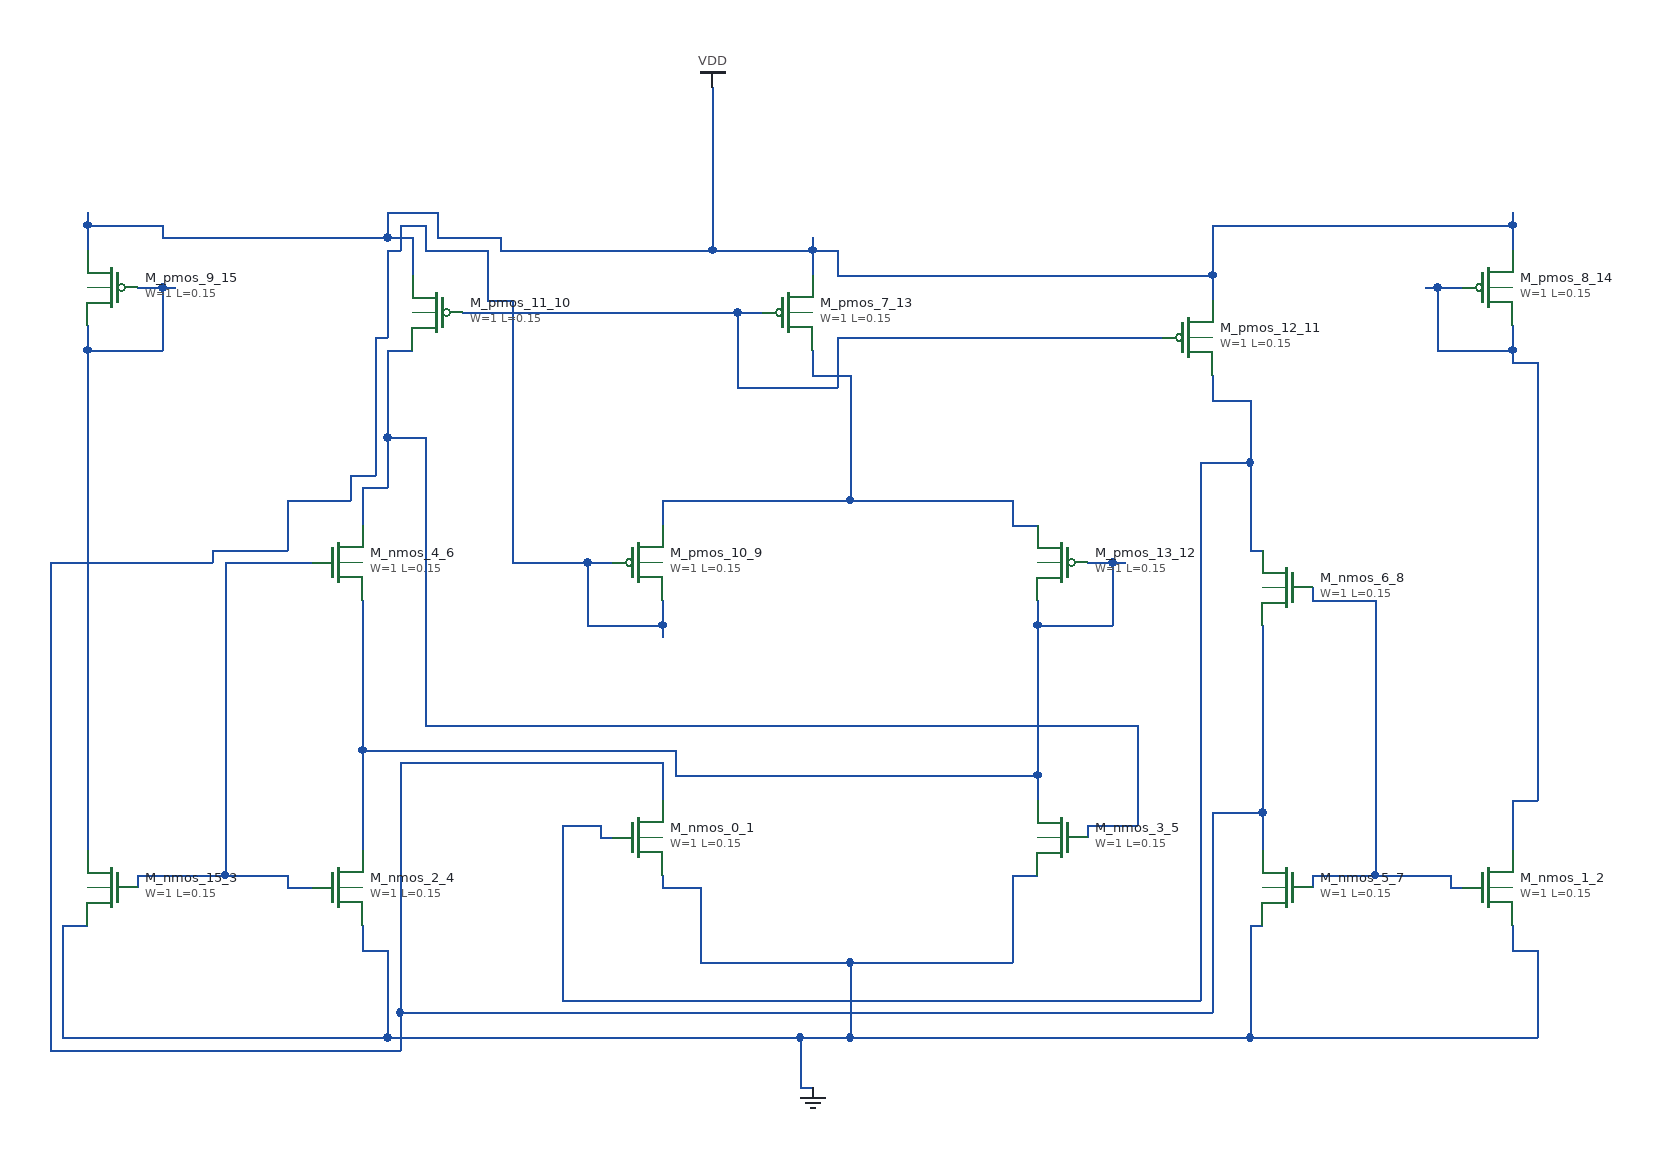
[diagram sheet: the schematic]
v {xschem version=3.4.8 file_version=1.2}
G {}
K {}
V {}
S {}
E {}
C {devices/gnd.sym} 660 880 0 0 {name="l_gnd_14_0" lab="GND"}
C {sky130_fd_pr/nfet3_01v8.sym} 520 680 0 0 {name="M_nmos_0_1"
W=1
L=0.15
body=GND
nf=1
mult=1
ad="expr('int((@nf + 1)/2) * @W / @nf * 0.29')"
pd="expr('2*int((@nf + 1)/2) * (@W / @nf + 0.29)')"
as="expr('int((@nf + 2)/2) * @W / @nf * 0.29')"
ps="expr('2*int((@nf + 2)/2) * (@W / @nf + 0.29)')"
nrd="expr('0.29 / @W ')" nrs="expr('0.29 / @W ')"
sa=0 sb=0 sd=0
model=nfet_01v8
spiceprefix=X
}
C {sky130_fd_pr/nfet3_01v8.sym} 1200 720 0 0 {name="M_nmos_1_2"
W=1
L=0.15
body=GND
nf=1
mult=1
ad="expr('int((@nf + 1)/2) * @W / @nf * 0.29')"
pd="expr('2*int((@nf + 1)/2) * (@W / @nf + 0.29)')"
as="expr('int((@nf + 2)/2) * @W / @nf * 0.29')"
ps="expr('2*int((@nf + 2)/2) * (@W / @nf + 0.29)')"
nrd="expr('0.29 / @W ')" nrs="expr('0.29 / @W ')"
sa=0 sb=0 sd=0
model=nfet_01v8
spiceprefix=X
}
C {sky130_fd_pr/nfet3_01v8.sym} 100 720 0 1 {name="M_nmos_15_3"
W=1
L=0.15
body=GND
nf=1
mult=1
ad="expr('int((@nf + 1)/2) * @W / @nf * 0.29')"
pd="expr('2*int((@nf + 1)/2) * (@W / @nf + 0.29)')"
as="expr('int((@nf + 2)/2) * @W / @nf * 0.29')"
ps="expr('2*int((@nf + 2)/2) * (@W / @nf + 0.29)')"
nrd="expr('0.29 / @W ')" nrs="expr('0.29 / @W ')"
sa=0 sb=0 sd=0
model=nfet_01v8
spiceprefix=X
}
C {sky130_fd_pr/nfet3_01v8.sym} 280 720 0 0 {name="M_nmos_2_4"
W=1
L=0.15
body=GND
nf=1
mult=1
ad="expr('int((@nf + 1)/2) * @W / @nf * 0.29')"
pd="expr('2*int((@nf + 1)/2) * (@W / @nf + 0.29)')"
as="expr('int((@nf + 2)/2) * @W / @nf * 0.29')"
ps="expr('2*int((@nf + 2)/2) * (@W / @nf + 0.29)')"
nrd="expr('0.29 / @W ')" nrs="expr('0.29 / @W ')"
sa=0 sb=0 sd=0
model=nfet_01v8
spiceprefix=X
}
C {sky130_fd_pr/nfet3_01v8.sym} 860 680 0 1 {name="M_nmos_3_5"
W=1
L=0.15
body=GND
nf=1
mult=1
ad="expr('int((@nf + 1)/2) * @W / @nf * 0.29')"
pd="expr('2*int((@nf + 1)/2) * (@W / @nf + 0.29)')"
as="expr('int((@nf + 2)/2) * @W / @nf * 0.29')"
ps="expr('2*int((@nf + 2)/2) * (@W / @nf + 0.29)')"
nrd="expr('0.29 / @W ')" nrs="expr('0.29 / @W ')"
sa=0 sb=0 sd=0
model=nfet_01v8
spiceprefix=X
}
C {sky130_fd_pr/nfet3_01v8.sym} 280 460 0 0 {name="M_nmos_4_6"
W=1
L=0.15
body=GND
nf=1
mult=1
ad="expr('int((@nf + 1)/2) * @W / @nf * 0.29')"
pd="expr('2*int((@nf + 1)/2) * (@W / @nf + 0.29)')"
as="expr('int((@nf + 2)/2) * @W / @nf * 0.29')"
ps="expr('2*int((@nf + 2)/2) * (@W / @nf + 0.29)')"
nrd="expr('0.29 / @W ')" nrs="expr('0.29 / @W ')"
sa=0 sb=0 sd=0
model=nfet_01v8
spiceprefix=X
}
C {sky130_fd_pr/nfet3_01v8.sym} 1040 720 0 1 {name="M_nmos_5_7"
W=1
L=0.15
body=GND
nf=1
mult=1
ad="expr('int((@nf + 1)/2) * @W / @nf * 0.29')"
pd="expr('2*int((@nf + 1)/2) * (@W / @nf + 0.29)')"
as="expr('int((@nf + 2)/2) * @W / @nf * 0.29')"
ps="expr('2*int((@nf + 2)/2) * (@W / @nf + 0.29)')"
nrd="expr('0.29 / @W ')" nrs="expr('0.29 / @W ')"
sa=0 sb=0 sd=0
model=nfet_01v8
spiceprefix=X
}
C {sky130_fd_pr/nfet3_01v8.sym} 1040 480 0 1 {name="M_nmos_6_8"
W=1
L=0.15
body=GND
nf=1
mult=1
ad="expr('int((@nf + 1)/2) * @W / @nf * 0.29')"
pd="expr('2*int((@nf + 1)/2) * (@W / @nf + 0.29)')"
as="expr('int((@nf + 2)/2) * @W / @nf * 0.29')"
ps="expr('2*int((@nf + 2)/2) * (@W / @nf + 0.29)')"
nrd="expr('0.29 / @W ')" nrs="expr('0.29 / @W ')"
sa=0 sb=0 sd=0
model=nfet_01v8
spiceprefix=X
}
C {sky130_fd_pr/pfet3_01v8.sym} 520 460 0 0 {name="M_pmos_10_9"
W=1
L=0.15
body=VDD
nf=1
mult=1
ad="expr('int((@nf + 1)/2) * @W / @nf * 0.29')"
pd="expr('2*int((@nf + 1)/2) * (@W / @nf + 0.29)')"
as="expr('int((@nf + 2)/2) * @W / @nf * 0.29')"
ps="expr('2*int((@nf + 2)/2) * (@W / @nf + 0.29)')"
nrd="expr('0.29 / @W ')" nrs="expr('0.29 / @W ')"
sa=0 sb=0 sd=0
model=pfet_01v8
spiceprefix=X
}
C {sky130_fd_pr/pfet3_01v8.sym} 360 260 0 1 {name="M_pmos_11_10"
W=1
L=0.15
body=VDD
nf=1
mult=1
ad="expr('int((@nf + 1)/2) * @W / @nf * 0.29')"
pd="expr('2*int((@nf + 1)/2) * (@W / @nf + 0.29)')"
as="expr('int((@nf + 2)/2) * @W / @nf * 0.29')"
ps="expr('2*int((@nf + 2)/2) * (@W / @nf + 0.29)')"
nrd="expr('0.29 / @W ')" nrs="expr('0.29 / @W ')"
sa=0 sb=0 sd=0
model=pfet_01v8
spiceprefix=X
}
C {sky130_fd_pr/pfet3_01v8.sym} 960 280 0 0 {name="M_pmos_12_11"
W=1
L=0.15
body=VDD
nf=1
mult=1
ad="expr('int((@nf + 1)/2) * @W / @nf * 0.29')"
pd="expr('2*int((@nf + 1)/2) * (@W / @nf + 0.29)')"
as="expr('int((@nf + 2)/2) * @W / @nf * 0.29')"
ps="expr('2*int((@nf + 2)/2) * (@W / @nf + 0.29)')"
nrd="expr('0.29 / @W ')" nrs="expr('0.29 / @W ')"
sa=0 sb=0 sd=0
model=pfet_01v8
spiceprefix=X
}
C {sky130_fd_pr/pfet3_01v8.sym} 860 460 0 1 {name="M_pmos_13_12"
W=1
L=0.15
body=VDD
nf=1
mult=1
ad="expr('int((@nf + 1)/2) * @W / @nf * 0.29')"
pd="expr('2*int((@nf + 1)/2) * (@W / @nf + 0.29)')"
as="expr('int((@nf + 2)/2) * @W / @nf * 0.29')"
ps="expr('2*int((@nf + 2)/2) * (@W / @nf + 0.29)')"
nrd="expr('0.29 / @W ')" nrs="expr('0.29 / @W ')"
sa=0 sb=0 sd=0
model=pfet_01v8
spiceprefix=X
}
C {sky130_fd_pr/pfet3_01v8.sym} 640 260 0 0 {name="M_pmos_7_13"
W=1
L=0.15
body=VDD
nf=1
mult=1
ad="expr('int((@nf + 1)/2) * @W / @nf * 0.29')"
pd="expr('2*int((@nf + 1)/2) * (@W / @nf + 0.29)')"
as="expr('int((@nf + 2)/2) * @W / @nf * 0.29')"
ps="expr('2*int((@nf + 2)/2) * (@W / @nf + 0.29)')"
nrd="expr('0.29 / @W ')" nrs="expr('0.29 / @W ')"
sa=0 sb=0 sd=0
model=pfet_01v8
spiceprefix=X
}
C {sky130_fd_pr/pfet3_01v8.sym} 1200 240 0 0 {name="M_pmos_8_14"
W=1
L=0.15
body=VDD
nf=1
mult=1
ad="expr('int((@nf + 1)/2) * @W / @nf * 0.29')"
pd="expr('2*int((@nf + 1)/2) * (@W / @nf + 0.29)')"
as="expr('int((@nf + 2)/2) * @W / @nf * 0.29')"
ps="expr('2*int((@nf + 2)/2) * (@W / @nf + 0.29)')"
nrd="expr('0.29 / @W ')" nrs="expr('0.29 / @W ')"
sa=0 sb=0 sd=0
model=pfet_01v8
spiceprefix=X
}
C {sky130_fd_pr/pfet3_01v8.sym} 100 240 0 1 {name="M_pmos_9_15"
W=1
L=0.15
body=VDD
nf=1
mult=1
ad="expr('int((@nf + 1)/2) * @W / @nf * 0.29')"
pd="expr('2*int((@nf + 1)/2) * (@W / @nf + 0.29)')"
as="expr('int((@nf + 2)/2) * @W / @nf * 0.29')"
ps="expr('2*int((@nf + 2)/2) * (@W / @nf + 0.29)')"
nrd="expr('0.29 / @W ')" nrs="expr('0.29 / @W ')"
sa=0 sb=0 sd=0
model=pfet_01v8
spiceprefix=X
}
C {devices/vdd.sym} 580 80 0 0 {name="l_vdd_16_16" lab="VDD"}
N 650 880 660 880 {}
N 60 840 320 840 {}
N 320 840 650 840 {}
N 650 840 690 840 {}
N 690 840 1010 840 {}
N 1010 840 1240 840 {}
N 570 780 690 780 {}
N 690 780 820 780 {}
N 300 770 320 770 {}
N 1220 770 1240 770 {}
N 60 750 80 750 {}
N 1010 750 1020 750 {}
N 540 720 570 720 {}
N 820 710 840 710 {}
N 60 840 60 750 {}
N 300 770 300 750 {}
N 320 840 320 770 {}
N 540 720 540 710 {}
N 570 780 570 720 {}
N 650 880 650 840 {}
N 690 840 690 780 {}
N 820 780 820 710 {}
N 1010 840 1010 750 {}
N 1220 770 1220 750 {}
N 1240 840 1240 770 {}
N 240 720 260 720 {}
N 120 710 190 710 {}
N 190 710 240 710 {}
N 190 460 260 460 {}
N 120 720 120 710 {}
N 190 710 190 460 {}
N 240 720 240 710 {}
N 550 630 840 630 {}
N 300 610 550 610 {}
N 840 510 900 510 {}
N 880 460 900 460 {}
N 900 460 910 460 {}
N 300 690 300 610 {}
N 300 610 300 490 {}
N 550 630 550 610 {}
N 840 650 840 630 {}
N 840 630 840 510 {}
N 840 510 840 490 {}
N 900 510 900 460 {}
N 50 850 330 850 {}
N 330 820 980 820 {}
N 980 660 1020 660 {}
N 330 620 540 620 {}
N 480 510 540 510 {}
N 50 460 180 460 {}
N 420 460 480 460 {}
N 480 460 500 460 {}
N 180 450 240 450 {}
N 240 410 290 410 {}
N 290 390 310 390 {}
N 310 280 320 280 {}
N 400 250 420 250 {}
N 320 210 330 210 {}
N 350 210 400 210 {}
N 330 190 350 190 {}
N 50 850 50 460 {}
N 180 460 180 450 {}
N 240 450 240 410 {}
N 290 410 290 390 {}
N 310 390 310 280 {}
N 320 280 320 210 {}
N 330 850 330 820 {}
N 330 820 330 620 {}
N 330 210 330 190 {}
N 350 210 350 190 {}
N 400 250 400 210 {}
N 420 460 420 250 {}
N 480 510 480 460 {}
N 540 650 540 620 {}
N 540 520 540 510 {}
N 540 510 540 490 {}
N 980 820 980 660 {}
N 1020 690 1020 660 {}
N 1020 660 1020 510 {}
N 880 670 920 670 {}
N 350 590 920 590 {}
N 300 400 320 400 {}
N 320 360 350 360 {}
N 320 290 340 290 {}
N 300 430 300 400 {}
N 320 400 320 360 {}
N 320 360 320 290 {}
N 350 590 350 360 {}
N 880 680 880 670 {}
N 920 670 920 590 {}
N 1170 720 1180 720 {}
N 1060 710 1110 710 {}
N 1110 710 1170 710 {}
N 1060 490 1110 490 {}
N 1060 720 1060 710 {}
N 1060 490 1060 480 {}
N 1110 710 1110 490 {}
N 1170 720 1170 710 {}
N 460 810 970 810 {}
N 490 680 500 680 {}
N 460 670 490 670 {}
N 1010 450 1020 450 {}
N 970 380 1010 380 {}
N 980 330 1010 330 {}
N 460 810 460 670 {}
N 490 680 490 670 {}
N 970 810 970 380 {}
N 980 330 980 310 {}
N 1010 450 1010 380 {}
N 1010 380 1010 330 {}
N 820 430 840 430 {}
N 540 410 690 410 {}
N 690 410 820 410 {}
N 660 310 690 310 {}
N 540 430 540 410 {}
N 660 310 660 290 {}
N 690 410 690 310 {}
N 820 430 820 410 {}
N 680 230 980 230 {}
N 410 210 580 210 {}
N 580 210 660 210 {}
N 660 210 680 210 {}
N 140 200 320 200 {}
N 320 200 340 200 {}
N 360 200 410 200 {}
N 80 190 140 190 {}
N 980 190 1220 190 {}
N 320 180 360 180 {}
N 80 210 80 190 {}
N 80 190 80 180 {}
N 140 200 140 190 {}
N 320 200 320 180 {}
N 340 230 340 200 {}
N 360 200 360 180 {}
N 410 210 410 200 {}
N 580 210 580 80 {}
N 660 230 660 210 {}
N 660 210 660 200 {}
N 680 230 680 210 {}
N 980 250 980 230 {}
N 980 230 980 190 {}
N 1220 210 1220 190 {}
N 1220 190 1220 180 {}
N 600 320 680 320 {}
N 680 280 940 280 {}
N 380 260 600 260 {}
N 600 260 620 260 {}
N 600 320 600 260 {}
N 680 320 680 280 {}
N 1220 650 1240 650 {}
N 1220 300 1240 300 {}
N 1160 290 1220 290 {}
N 1150 240 1160 240 {}
N 1160 240 1180 240 {}
N 1160 290 1160 240 {}
N 1220 690 1220 650 {}
N 1220 300 1220 290 {}
N 1220 290 1220 270 {}
N 1240 650 1240 300 {}
N 80 290 140 290 {}
N 120 240 140 240 {}
N 140 240 150 240 {}
N 80 690 80 290 {}
N 80 290 80 270 {}
N 140 290 140 240 {}
